VERSION 5.8 ;
BUSBITCHARS "[]" ;
DIVIDERCHAR "/" ;
UNITS
  DATABASE MICRONS 1000 ;
END UNITS
MANUFACTURINGGRID 0.005 ;
SITE core
  CLASS CORE ;
  SYMMETRY Y ;
  SIZE 0.2 BY 1.4 ;
END core
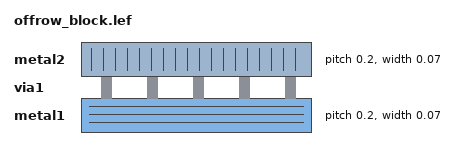
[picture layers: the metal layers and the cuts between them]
LAYER metal1
  TYPE ROUTING ;
  DIRECTION HORIZONTAL ;
  PITCH 0.2 ;
  WIDTH 0.07 ;
END metal1
LAYER via1
  TYPE CUT ;
END via1
LAYER metal2
  TYPE ROUTING ;
  DIRECTION VERTICAL ;
  PITCH 0.2 ;
  WIDTH 0.07 ;
END metal2
MACRO INV
  CLASS CORE ;
  ORIGIN 0 0 ;
  SIZE 0.6 BY 1.4 ;
  SYMMETRY X Y ;
  SITE core ;
END INV
# 4.3 um tall: not a whole number of 1.4 um rows
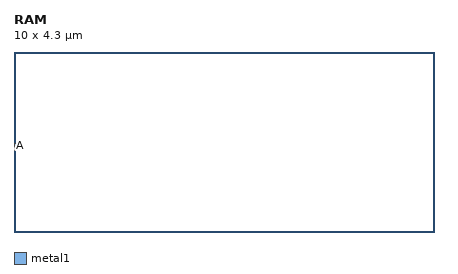
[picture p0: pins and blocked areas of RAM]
MACRO RAM
  CLASS BLOCK ;
  ORIGIN 0 0 ;
  SIZE 10 BY 4.3 ;
  SYMMETRY X Y ;
  PIN A
    DIRECTION INPUT ;
    USE SIGNAL ;
    PORT
      LAYER metal1 ;
        RECT 0 2 0.1 2.1 ;
    END
  END A
END RAM
END LIBRARY
